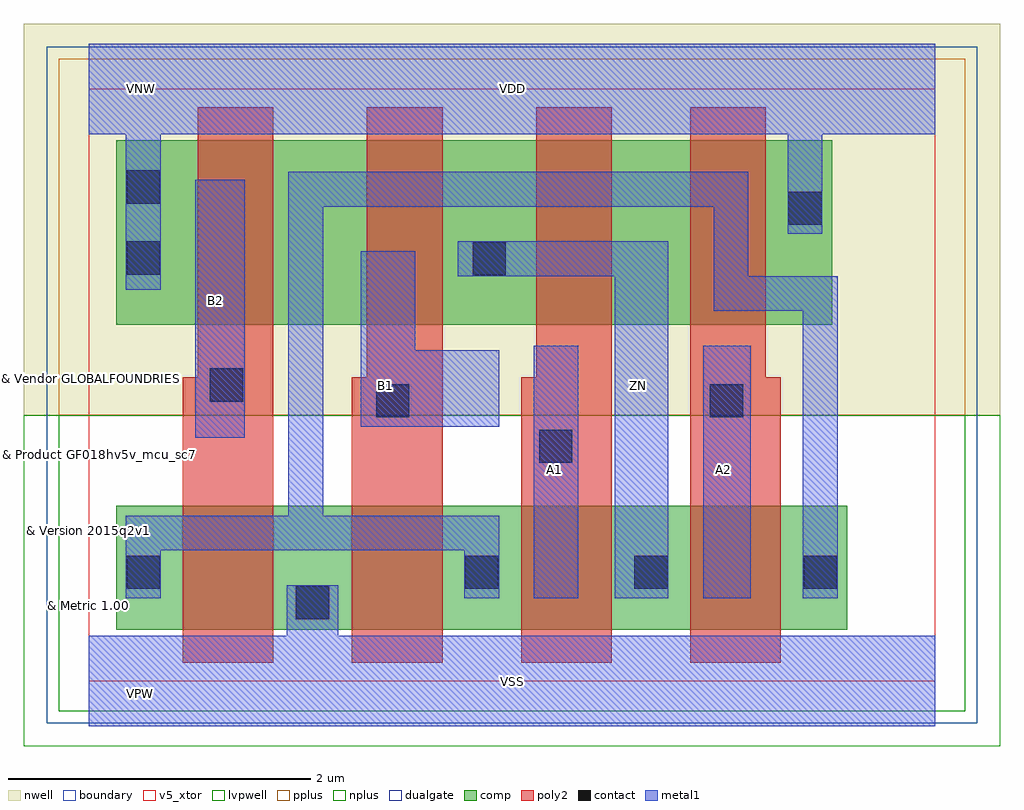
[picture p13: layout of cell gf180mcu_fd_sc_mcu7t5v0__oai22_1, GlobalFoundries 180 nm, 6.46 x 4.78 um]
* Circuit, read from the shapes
.subckt gf180mcu_fd_sc_mcu7t5v0__oai22_1 A1 A2 B1 B2 VDD VNW VSS ZN
XM1 VSS B2 n1 VSUBS nfet_05v0 w=0.82u l=0.6u
XM2 n1 B1 VSS VSUBS nfet_05v0 w=0.82u l=0.6u
XM3 ZN A1 n1 VSUBS nfet_05v0 w=0.82u l=0.6u
XM4 n1 A2 ZN VSUBS nfet_05v0 w=0.82u l=0.6u
XM5 n2 B2 VDD VNW pfet_05v0 w=1.22u l=0.5u
XM6 ZN B1 n2 VNW pfet_05v0 w=1.22u l=0.5u
XM7 n3 A1 ZN VNW pfet_05v0 w=1.22u l=0.5u
XM8 VDD A2 n3 VNW pfet_05v0 w=1.22u l=0.5u
.ends

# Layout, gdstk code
import gdstk
lib = gdstk.Library(unit=1e-6, precision=1e-09)
def R(c, l, rs):  # rectangles x0, y0, x1, y1
    for r in rs: c.add(gdstk.rectangle(r[:2], r[2:], *l))
def A(c, l, x, y, w, h, nx, ny, dx, dy):  # array of equal rectangles
    R(c, l, [(x+i*dx, y+j*dy, x+i*dx+w, y+j*dy+h) for i in range(nx) for j in range(ny)])
def P(c, l, *ps):  # polygons
    for p in ps: c.add(gdstk.Polygon(p, *l))
boundary = (0, 0)
nwell = (21, 0)
comp = (22, 0)
poly2 = (30, 0)
pplus = (31, 0)
nplus = (32, 0)
contact = (33, 0)
metal1 = (34, 0)
dualgate = (55, 0)
v5_xtor = (112, 1)
lvpwell = (204, 0)

gf180mcu_fd_sc_mcu7t5v0_ = lib.new_cell('gf180mcu_fd_sc_mcu7t5v0__oai22_1')
R(gf180mcu_fd_sc_mcu7t5v0_, boundary, [(0,0,5.6,3.92)])
R(gf180mcu_fd_sc_mcu7t5v0_, nwell, [(-0.43,1.76,6.03,4.35)])
R(gf180mcu_fd_sc_mcu7t5v0_, comp, [(0.18,0.34,5.02,1.16), (0.18,2.36,4.92,3.58)])
P(gf180mcu_fd_sc_mcu7t5v0_, poly2, [(0.62,0.12),(0.62,2.01),(0.72,2.01),(0.72,3.8),(1.22,3.8),(1.22,0.12)],
  [(1.74,0.12),(1.74,2.01),(1.84,2.01),(1.84,3.8),(2.34,3.8),(2.34,0.12)],
  [(2.86,0.12),(2.86,2.01),(2.96,2.01),(2.96,3.8),(3.46,3.8),(3.46,0.12)],
  [(3.98,0.12),(3.98,3.8),(4.48,3.8),(4.48,2.01),(4.58,2.01),(4.58,0.12)])
R(gf180mcu_fd_sc_mcu7t5v0_, pplus, [(-0.2,1.76,5.8,4.12)])
R(gf180mcu_fd_sc_mcu7t5v0_, nplus, [(-0.2,-0.2,5.8,1.76)])
A(gf180mcu_fd_sc_mcu7t5v0_, contact, 2.49, 0.61, 0.22, 0.22, 3, 1, 1.12, 0)
R(gf180mcu_fd_sc_mcu7t5v0_, contact, [(1.37,0.41,1.59,0.63), (0.25,0.61,0.47,0.83), (2.98,1.445,3.2,1.665), (1.9,1.745,2.12,1.965), (4.11,1.745,4.33,1.965), (0.8,1.85,1.02,2.07), (2.54,2.685,2.76,2.905), (0.25,2.69,0.47,2.91), (4.63,3.02,4.85,3.24), (0.25,3.16,0.47,3.38)])
R(gf180mcu_fd_sc_mcu7t5v0_, metal1, [(2.945,0.55,3.24,2.22), (4.065,0.55,4.38,2.22), (0.705,1.61,1.03,3.32)])
P(gf180mcu_fd_sc_mcu7t5v0_, metal1, [(1.8,1.685),(1.8,2.845),(2.16,2.845),(2.16,2.19),(2.715,2.19),(2.715,1.685)],
  [(3.48,0.55),(3.48,2.68),(2.44,2.68),(2.44,2.91),(3.835,2.91),(3.835,0.55)],
  [(0.245,0.55),(0.245,1.095),(1.32,1.095),(1.32,3.37),(4.365,3.37),(4.365,2.68),(4.955,2.68),(4.955,0.55),(4.725,0.55),(4.725,2.45),(4.135,2.45),(4.135,3.14),(1.55,3.14),(1.55,1.095),(2.715,1.095),(2.715,0.55),(2.485,0.55),(2.485,0.865),(0.475,0.865),(0.475,0.55)],
  [(0,-0.3),(0,0.3),(1.31,0.3),(1.31,0.635),(1.65,0.635),(1.65,0.3),(5.6,0.3),(5.6,-0.3)],
  [(0.245,2.59),(0.245,3.62),(0,3.62),(0,4.22),(5.6,4.22),(5.6,3.62),(4.855,3.62),(4.855,2.96),(4.625,2.96),(4.625,3.62),(0.475,3.62),(0.475,2.59)])
R(gf180mcu_fd_sc_mcu7t5v0_, dualgate, [(-0.28,-0.28,5.88,4.2)])
R(gf180mcu_fd_sc_mcu7t5v0_, v5_xtor, [(0,0,5.6,3.92)])
R(gf180mcu_fd_sc_mcu7t5v0_, lvpwell, [(-0.43,-0.43,6.03,1.76)])
gf180mcu_fd_sc_mcu7t5v0_.add(gdstk.Label('A2', (4.2,1.4), layer=34, texttype=10))
gf180mcu_fd_sc_mcu7t5v0_.add(gdstk.Label('B1', (1.96,1.96), layer=34, texttype=10))
gf180mcu_fd_sc_mcu7t5v0_.add(gdstk.Label('B2', (0.84,2.52), layer=34, texttype=10))
gf180mcu_fd_sc_mcu7t5v0_.add(gdstk.Label('VDD', (2.8,3.92), layer=34, texttype=10))
gf180mcu_fd_sc_mcu7t5v0_.add(gdstk.Label('VSS', (2.8,0), layer=34, texttype=10))
gf180mcu_fd_sc_mcu7t5v0_.add(gdstk.Label('ZN', (3.64,1.96), layer=34, texttype=10))
gf180mcu_fd_sc_mcu7t5v0_.add(gdstk.Label('A1', (3.08,1.4), layer=34, texttype=10))
gf180mcu_fd_sc_mcu7t5v0_.add(gdstk.Label('& Vendor GLOBALFOUNDRIES', (0,2), layer=63, texttype=63))
gf180mcu_fd_sc_mcu7t5v0_.add(gdstk.Label('& Product GF018hv5v_mcu_sc7', (0,1.5), layer=63, texttype=63))
gf180mcu_fd_sc_mcu7t5v0_.add(gdstk.Label('& Version 2015q2v1', (0,1), layer=63, texttype=63))
gf180mcu_fd_sc_mcu7t5v0_.add(gdstk.Label('& Metric 1.00', (0,0.5), layer=63, texttype=63))
gf180mcu_fd_sc_mcu7t5v0_.add(gdstk.Label('VNW', (0.345,3.92), layer=21, texttype=10))
gf180mcu_fd_sc_mcu7t5v0_.add(gdstk.Label('VPW', (0.34,-0.085), layer=204, texttype=10))

lib.write_gds('gf180mcu_fd_sc_mcu7t5v0__oai22_1.gds')
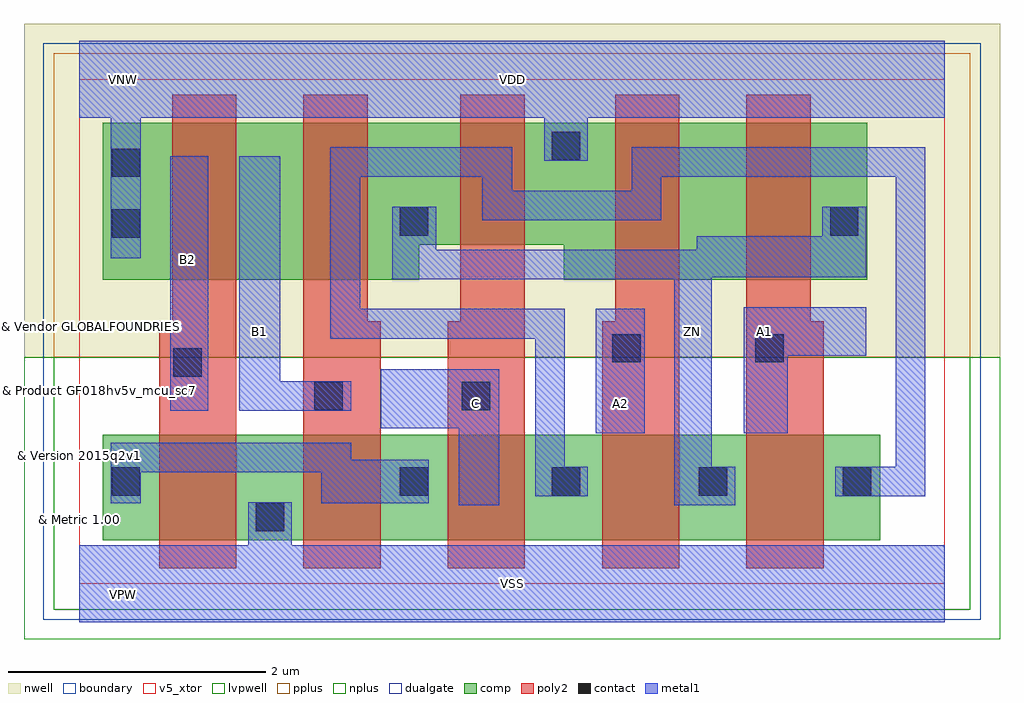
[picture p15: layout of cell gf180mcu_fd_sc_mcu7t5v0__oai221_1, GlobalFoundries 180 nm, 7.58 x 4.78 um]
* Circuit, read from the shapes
.subckt gf180mcu_fd_sc_mcu7t5v0__oai221_1 A1 A2 B1 B2 C VDD VNW VSS ZN
XM1 VSS B2 n1 VSUBS nfet_05v0 w=0.82u l=0.6u
XM2 n1 B1 VSS VSUBS nfet_05v0 w=0.82u l=0.6u
XM3 n2 C n1 VSUBS nfet_05v0 w=0.82u l=0.6u
XM4 ZN A2 n2 VSUBS nfet_05v0 w=0.82u l=0.6u
XM5 n2 A1 ZN VSUBS nfet_05v0 w=0.82u l=0.6u
XM6 n3 B2 VDD VNW pfet_05v0 w=1.22u l=0.5u
XM7 ZN B1 n3 VNW pfet_05v0 w=1.22u l=0.5u
XM8 VDD C ZN VNW pfet_05v0 w=0.945u l=0.5u
XM9 n4 A2 VDD VNW pfet_05v0 w=1.22u l=0.5u
XM10 ZN A1 n4 VNW pfet_05v0 w=1.22u l=0.5u
.ends

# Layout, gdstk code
import gdstk
lib = gdstk.Library(unit=1e-6, precision=1e-09)
def R(c, l, rs):  # rectangles x0, y0, x1, y1
    for r in rs: c.add(gdstk.rectangle(r[:2], r[2:], *l))
def P(c, l, *ps):  # polygons
    for p in ps: c.add(gdstk.Polygon(p, *l))
boundary = (0, 0)
nwell = (21, 0)
comp = (22, 0)
poly2 = (30, 0)
pplus = (31, 0)
nplus = (32, 0)
contact = (33, 0)
metal1 = (34, 0)
dualgate = (55, 0)
v5_xtor = (112, 1)
lvpwell = (204, 0)

gf180mcu_fd_sc_mcu7t5v0_ = lib.new_cell('gf180mcu_fd_sc_mcu7t5v0__oai221_1')
R(gf180mcu_fd_sc_mcu7t5v0_, boundary, [(0,0,6.72,3.92)])
R(gf180mcu_fd_sc_mcu7t5v0_, nwell, [(-0.43,1.76,7.15,4.35)])
R(gf180mcu_fd_sc_mcu7t5v0_, comp, [(0.18,0.34,6.22,1.16)])
P(gf180mcu_fd_sc_mcu7t5v0_, comp, [(0.18,2.36),(0.18,3.58),(6.12,3.58),(6.12,2.36),(3.76,2.36),(3.76,2.635),(2.64,2.635),(2.64,2.36)])
P(gf180mcu_fd_sc_mcu7t5v0_, poly2, [(0.62,0.12),(0.62,2.04),(0.72,2.04),(0.72,3.8),(1.22,3.8),(1.22,0.12)],
  [(1.74,0.12),(1.74,3.8),(2.24,3.8),(2.24,2.04),(2.34,2.04),(2.34,0.12)],
  [(2.86,0.12),(2.86,2.04),(2.96,2.04),(2.96,3.8),(3.46,3.8),(3.46,0.12)],
  [(4.06,0.12),(4.06,2.04),(4.16,2.04),(4.16,3.8),(4.66,3.8),(4.66,0.12)],
  [(5.18,0.12),(5.18,3.8),(5.68,3.8),(5.68,2.04),(5.78,2.04),(5.78,0.12)])
R(gf180mcu_fd_sc_mcu7t5v0_, pplus, [(-0.2,1.76,6.92,4.12)])
R(gf180mcu_fd_sc_mcu7t5v0_, nplus, [(-0.2,-0.2,6.92,1.76)])
R(gf180mcu_fd_sc_mcu7t5v0_, contact, [(1.37,0.41,1.59,0.63), (0.25,0.685,0.47,0.905), (2.49,0.685,2.71,0.905), (3.67,0.685,3.89,0.905), (4.81,0.685,5.03,0.905), (5.93,0.685,6.15,0.905), (1.825,1.35,2.045,1.57), (2.97,1.35,3.19,1.57), (0.73,1.61,0.95,1.83), (4.14,1.72,4.36,1.94), (5.25,1.72,5.47,1.94), (0.25,2.69,0.47,2.91), (2.49,2.705,2.71,2.925), (5.83,2.705,6.05,2.925), (0.25,3.16,0.47,3.38), (3.67,3.29,3.89,3.51)])
R(gf180mcu_fd_sc_mcu7t5v0_, metal1, [(4.01,1.17,4.39,2.135), (0.705,1.345,1,3.32)])
P(gf180mcu_fd_sc_mcu7t5v0_, metal1, [(1.24,1.345),(1.24,3.32),(1.56,3.32),(1.56,1.575),(2.11,1.575),(2.11,1.345)],
  [(0.245,0.625),(0.245,1.095),(2.11,1.095),(2.11,0.965),(2.715,0.965),(2.715,0.625),(1.88,0.625),(1.88,0.865),(0.475,0.865),(0.475,0.625)],
  [(2.945,0.61),(2.945,1.21),(2.34,1.21),(2.34,1.665),(3.26,1.665),(3.26,0.61)],
  [(5.16,1.17),(5.16,2.15),(6.11,2.15),(6.11,1.77),(5.5,1.77),(5.5,1.17)],
  [(4.62,0.61),(4.62,2.365),(2.43,2.365),(2.43,2.93),(2.77,2.93),(2.77,2.595),(4.795,2.595),(4.795,2.7),(5.77,2.7),(5.77,2.93),(6.11,2.93),(6.11,2.38),(4.91,2.38),(4.91,0.91),(5.095,0.91),(5.095,0.61)],
  [(3.54,0.68),(3.54,1.905),(1.95,1.905),(1.95,3.39),(3.36,3.39),(3.36,3.055),(4.29,3.055),(4.29,3.39),(6.57,3.39),(6.57,0.68),(5.87,0.68),(5.87,0.91),(6.34,0.91),(6.34,3.16),(4.52,3.16),(4.52,2.825),(3.13,2.825),(3.13,3.16),(2.18,3.16),(2.18,2.135),(3.77,2.135),(3.77,0.91),(3.95,0.91),(3.95,0.68)],
  [(0,-0.3),(0,0.3),(1.31,0.3),(1.31,0.635),(1.65,0.635),(1.65,0.3),(6.72,0.3),(6.72,-0.3)],
  [(0.245,2.53),(0.245,3.62),(0,3.62),(0,4.22),(6.72,4.22),(6.72,3.62),(3.95,3.62),(3.95,3.285),(3.61,3.285),(3.61,3.62),(0.475,3.62),(0.475,2.53)])
R(gf180mcu_fd_sc_mcu7t5v0_, dualgate, [(-0.28,-0.28,7,4.2)])
R(gf180mcu_fd_sc_mcu7t5v0_, v5_xtor, [(0,0,6.72,3.92)])
R(gf180mcu_fd_sc_mcu7t5v0_, lvpwell, [(-0.43,-0.43,7.15,1.76)])
gf180mcu_fd_sc_mcu7t5v0_.add(gdstk.Label('B1', (1.4,1.96), layer=34, texttype=10))
gf180mcu_fd_sc_mcu7t5v0_.add(gdstk.Label('C', (3.08,1.4), layer=34, texttype=10))
gf180mcu_fd_sc_mcu7t5v0_.add(gdstk.Label('VDD', (3.36,3.92), layer=34, texttype=10))
gf180mcu_fd_sc_mcu7t5v0_.add(gdstk.Label('VSS', (3.36,0), layer=34, texttype=10))
gf180mcu_fd_sc_mcu7t5v0_.add(gdstk.Label('ZN', (4.76,1.96), layer=34, texttype=10))
gf180mcu_fd_sc_mcu7t5v0_.add(gdstk.Label('A1', (5.32,1.96), layer=34, texttype=10))
gf180mcu_fd_sc_mcu7t5v0_.add(gdstk.Label('A2', (4.2,1.4), layer=34, texttype=10))
gf180mcu_fd_sc_mcu7t5v0_.add(gdstk.Label('B2', (0.84,2.52), layer=34, texttype=10))
gf180mcu_fd_sc_mcu7t5v0_.add(gdstk.Label('& Vendor GLOBALFOUNDRIES', (0,2), layer=63, texttype=63))
gf180mcu_fd_sc_mcu7t5v0_.add(gdstk.Label('& Product GF018hv5v_mcu_sc7', (0,1.5), layer=63, texttype=63))
gf180mcu_fd_sc_mcu7t5v0_.add(gdstk.Label('& Version 2015q2v1', (0,1), layer=63, texttype=63))
gf180mcu_fd_sc_mcu7t5v0_.add(gdstk.Label('& Metric 1.00', (0,0.5), layer=63, texttype=63))
gf180mcu_fd_sc_mcu7t5v0_.add(gdstk.Label('VNW', (0.345,3.92), layer=21, texttype=10))
gf180mcu_fd_sc_mcu7t5v0_.add(gdstk.Label('VPW', (0.34,-0.085), layer=204, texttype=10))

lib.write_gds('gf180mcu_fd_sc_mcu7t5v0__oai221_1.gds')
